VERSION 5.8 ;
BUSBITCHARS "[]" ;
DIVIDERCHAR "/" ;
UNITS
    DATABASE MICRONS 1000 ;
END UNITS

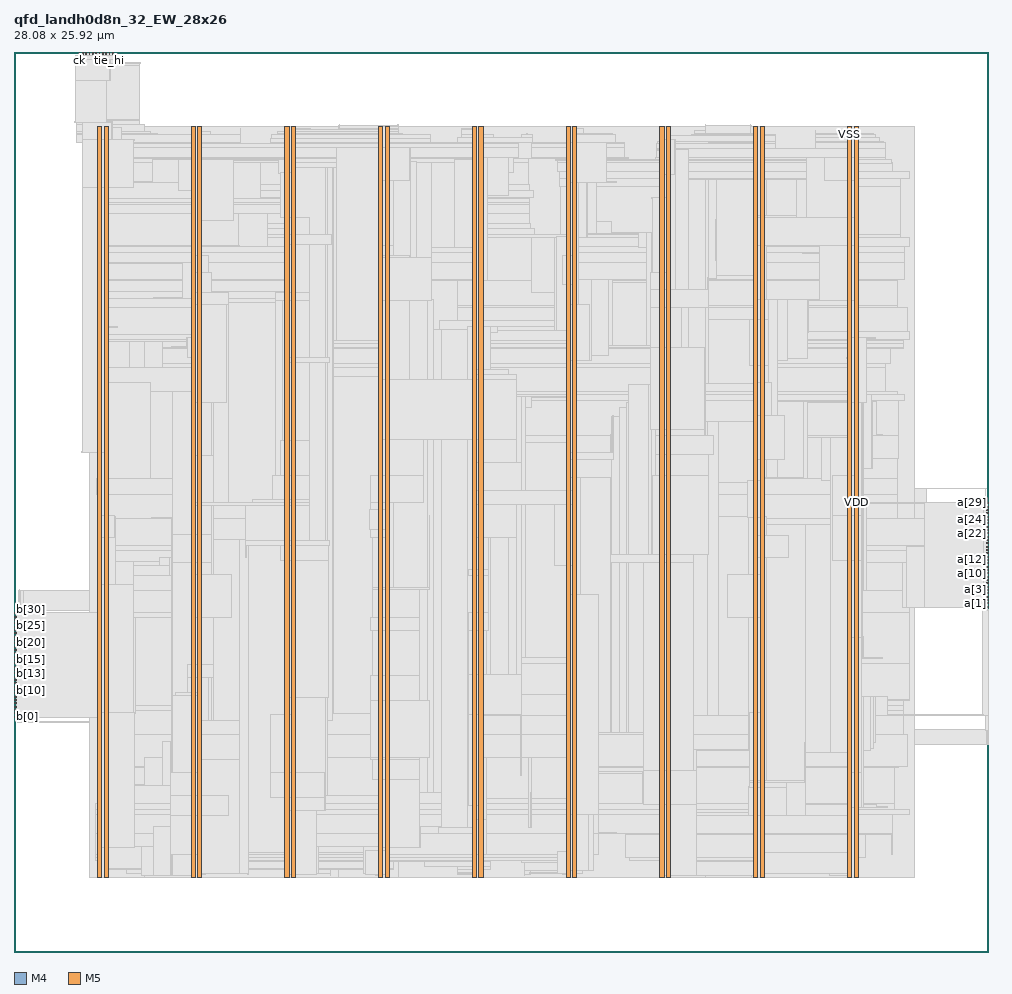
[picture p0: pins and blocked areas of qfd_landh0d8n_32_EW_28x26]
MACRO qfd_landh0d8n_32_EW_28x26
  FOREIGN qfd_landh0d8n_32_EW_28x26 0 0 ;
  CLASS BLOCK ;
  SIZE 28.08 BY 25.92 ;
  PIN a[0]
    DIRECTION INPUT ;
    USE SIGNAL ;
    PORT
      LAYER M4 ;
        RECT  27.996 9.936 28.08 9.96 ;
    END
  END a[0]
  PIN a[10]
    DIRECTION INPUT ;
    USE SIGNAL ;
    PORT
      LAYER M4 ;
        RECT  27.996 10.896 28.08 10.92 ;
    END
  END a[10]
  PIN a[11]
    DIRECTION INPUT ;
    USE SIGNAL ;
    PORT
      LAYER M4 ;
        RECT  27.996 10.992 28.08 11.016 ;
    END
  END a[11]
  PIN a[12]
    DIRECTION INPUT ;
    USE SIGNAL ;
    PORT
      LAYER M4 ;
        RECT  27.996 11.088 28.08 11.112 ;
    END
  END a[12]
  PIN a[13]
    DIRECTION INPUT ;
    USE SIGNAL ;
    PORT
      LAYER M4 ;
        RECT  27.996 11.184 28.08 11.208 ;
    END
  END a[13]
  PIN a[14]
    DIRECTION INPUT ;
    USE SIGNAL ;
    PORT
      LAYER M4 ;
        RECT  27.996 11.28 28.08 11.304 ;
    END
  END a[14]
  PIN a[15]
    DIRECTION INPUT ;
    USE SIGNAL ;
    PORT
      LAYER M4 ;
        RECT  27.996 11.376 28.08 11.4 ;
    END
  END a[15]
  PIN a[16]
    DIRECTION INPUT ;
    USE SIGNAL ;
    PORT
      LAYER M4 ;
        RECT  27.996 11.472 28.08 11.496 ;
    END
  END a[16]
  PIN a[17]
    DIRECTION INPUT ;
    USE SIGNAL ;
    PORT
      LAYER M4 ;
        RECT  27.996 11.568 28.08 11.592 ;
    END
  END a[17]
  PIN a[18]
    DIRECTION INPUT ;
    USE SIGNAL ;
    PORT
      LAYER M4 ;
        RECT  27.996 11.664 28.08 11.688 ;
    END
  END a[18]
  PIN a[19]
    DIRECTION INPUT ;
    USE SIGNAL ;
    PORT
      LAYER M4 ;
        RECT  27.996 11.76 28.08 11.784 ;
    END
  END a[19]
  PIN a[1]
    DIRECTION INPUT ;
    USE SIGNAL ;
    PORT
      LAYER M4 ;
        RECT  27.996 10.032 28.08 10.056 ;
    END
  END a[1]
  PIN a[20]
    DIRECTION INPUT ;
    USE SIGNAL ;
    PORT
      LAYER M4 ;
        RECT  27.996 11.856 28.08 11.88 ;
    END
  END a[20]
  PIN a[21]
    DIRECTION INPUT ;
    USE SIGNAL ;
    PORT
      LAYER M4 ;
        RECT  27.996 11.952 28.08 11.976 ;
    END
  END a[21]
  PIN a[22]
    DIRECTION INPUT ;
    USE SIGNAL ;
    PORT
      LAYER M4 ;
        RECT  27.996 12.048 28.08 12.072 ;
    END
  END a[22]
  PIN a[23]
    DIRECTION INPUT ;
    USE SIGNAL ;
    PORT
      LAYER M4 ;
        RECT  27.996 12.144 28.08 12.168 ;
    END
  END a[23]
  PIN a[24]
    DIRECTION INPUT ;
    USE SIGNAL ;
    PORT
      LAYER M4 ;
        RECT  27.996 12.24 28.08 12.264 ;
    END
  END a[24]
  PIN a[25]
    DIRECTION INPUT ;
    USE SIGNAL ;
    PORT
      LAYER M4 ;
        RECT  27.996 12.336 28.08 12.36 ;
    END
  END a[25]
  PIN a[26]
    DIRECTION INPUT ;
    USE SIGNAL ;
    PORT
      LAYER M4 ;
        RECT  27.996 12.432 28.08 12.456 ;
    END
  END a[26]
  PIN a[27]
    DIRECTION INPUT ;
    USE SIGNAL ;
    PORT
      LAYER M4 ;
        RECT  27.996 12.528 28.08 12.552 ;
    END
  END a[27]
  PIN a[28]
    DIRECTION INPUT ;
    USE SIGNAL ;
    PORT
      LAYER M4 ;
        RECT  27.996 12.624 28.08 12.648 ;
    END
  END a[28]
  PIN a[29]
    DIRECTION INPUT ;
    USE SIGNAL ;
    PORT
      LAYER M4 ;
        RECT  27.996 12.72 28.08 12.744 ;
    END
  END a[29]
  PIN a[2]
    DIRECTION INPUT ;
    USE SIGNAL ;
    PORT
      LAYER M4 ;
        RECT  27.996 10.128 28.08 10.152 ;
    END
  END a[2]
  PIN a[30]
    DIRECTION INPUT ;
    USE SIGNAL ;
    PORT
      LAYER M4 ;
        RECT  27.996 12.816 28.08 12.84 ;
    END
  END a[30]
  PIN a[31]
    DIRECTION INPUT ;
    USE SIGNAL ;
    PORT
      LAYER M4 ;
        RECT  27.996 12.912 28.08 12.936 ;
    END
  END a[31]
  PIN a[3]
    DIRECTION INPUT ;
    USE SIGNAL ;
    PORT
      LAYER M4 ;
        RECT  27.996 10.224 28.08 10.248 ;
    END
  END a[3]
  PIN a[4]
    DIRECTION INPUT ;
    USE SIGNAL ;
    PORT
      LAYER M4 ;
        RECT  27.996 10.32 28.08 10.344 ;
    END
  END a[4]
  PIN a[5]
    DIRECTION INPUT ;
    USE SIGNAL ;
    PORT
      LAYER M4 ;
        RECT  27.996 10.416 28.08 10.44 ;
    END
  END a[5]
  PIN a[6]
    DIRECTION INPUT ;
    USE SIGNAL ;
    PORT
      LAYER M4 ;
        RECT  27.996 10.512 28.08 10.536 ;
    END
  END a[6]
  PIN a[7]
    DIRECTION INPUT ;
    USE SIGNAL ;
    PORT
      LAYER M4 ;
        RECT  27.996 10.608 28.08 10.632 ;
    END
  END a[7]
  PIN a[8]
    DIRECTION INPUT ;
    USE SIGNAL ;
    PORT
      LAYER M4 ;
        RECT  27.996 10.704 28.08 10.728 ;
    END
  END a[8]
  PIN a[9]
    DIRECTION INPUT ;
    USE SIGNAL ;
    PORT
      LAYER M4 ;
        RECT  27.996 10.8 28.08 10.824 ;
    END
  END a[9]
  PIN b[0]
    DIRECTION OUTPUT ;
    USE SIGNAL ;
    PORT
      LAYER M4 ;
        RECT  0 6.768 0.084 6.792 ;
    END
  END b[0]
  PIN b[10]
    DIRECTION OUTPUT ;
    USE SIGNAL ;
    PORT
      LAYER M4 ;
        RECT  0 7.728 0.084 7.752 ;
    END
  END b[10]
  PIN b[11]
    DIRECTION OUTPUT ;
    USE SIGNAL ;
    PORT
      LAYER M4 ;
        RECT  0 7.824 0.084 7.848 ;
    END
  END b[11]
  PIN b[12]
    DIRECTION OUTPUT ;
    USE SIGNAL ;
    PORT
      LAYER M4 ;
        RECT  0 7.92 0.084 7.944 ;
    END
  END b[12]
  PIN b[13]
    DIRECTION OUTPUT ;
    USE SIGNAL ;
    PORT
      LAYER M4 ;
        RECT  0 8.016 0.084 8.04 ;
    END
  END b[13]
  PIN b[14]
    DIRECTION OUTPUT ;
    USE SIGNAL ;
    PORT
      LAYER M4 ;
        RECT  0 8.112 0.084 8.136 ;
    END
  END b[14]
  PIN b[15]
    DIRECTION OUTPUT ;
    USE SIGNAL ;
    PORT
      LAYER M4 ;
        RECT  0 8.208 0.084 8.232 ;
    END
  END b[15]
  PIN b[16]
    DIRECTION OUTPUT ;
    USE SIGNAL ;
    PORT
      LAYER M4 ;
        RECT  0 8.304 0.084 8.328 ;
    END
  END b[16]
  PIN b[17]
    DIRECTION OUTPUT ;
    USE SIGNAL ;
    PORT
      LAYER M4 ;
        RECT  0 8.4 0.084 8.424 ;
    END
  END b[17]
  PIN b[18]
    DIRECTION OUTPUT ;
    USE SIGNAL ;
    PORT
      LAYER M4 ;
        RECT  0 8.496 0.084 8.52 ;
    END
  END b[18]
  PIN b[19]
    DIRECTION OUTPUT ;
    USE SIGNAL ;
    PORT
      LAYER M4 ;
        RECT  0 8.592 0.084 8.616 ;
    END
  END b[19]
  PIN b[1]
    DIRECTION OUTPUT ;
    USE SIGNAL ;
    PORT
      LAYER M4 ;
        RECT  0 6.864 0.084 6.888 ;
    END
  END b[1]
  PIN b[20]
    DIRECTION OUTPUT ;
    USE SIGNAL ;
    PORT
      LAYER M4 ;
        RECT  0 8.688 0.084 8.712 ;
    END
  END b[20]
  PIN b[21]
    DIRECTION OUTPUT ;
    USE SIGNAL ;
    PORT
      LAYER M4 ;
        RECT  0 8.784 0.084 8.808 ;
    END
  END b[21]
  PIN b[22]
    DIRECTION OUTPUT ;
    USE SIGNAL ;
    PORT
      LAYER M4 ;
        RECT  0 8.88 0.084 8.904 ;
    END
  END b[22]
  PIN b[23]
    DIRECTION OUTPUT ;
    USE SIGNAL ;
    PORT
      LAYER M4 ;
        RECT  0 8.976 0.084 9 ;
    END
  END b[23]
  PIN b[24]
    DIRECTION OUTPUT ;
    USE SIGNAL ;
    PORT
      LAYER M4 ;
        RECT  0 9.072 0.084 9.096 ;
    END
  END b[24]
  PIN b[25]
    DIRECTION OUTPUT ;
    USE SIGNAL ;
    PORT
      LAYER M4 ;
        RECT  0 9.168 0.084 9.192 ;
    END
  END b[25]
  PIN b[26]
    DIRECTION OUTPUT ;
    USE SIGNAL ;
    PORT
      LAYER M4 ;
        RECT  0 9.264 0.084 9.288 ;
    END
  END b[26]
  PIN b[27]
    DIRECTION OUTPUT ;
    USE SIGNAL ;
    PORT
      LAYER M4 ;
        RECT  0 9.36 0.084 9.384 ;
    END
  END b[27]
  PIN b[28]
    DIRECTION OUTPUT ;
    USE SIGNAL ;
    PORT
      LAYER M4 ;
        RECT  0 9.456 0.084 9.48 ;
    END
  END b[28]
  PIN b[29]
    DIRECTION OUTPUT ;
    USE SIGNAL ;
    PORT
      LAYER M4 ;
        RECT  0 9.552 0.084 9.576 ;
    END
  END b[29]
  PIN b[2]
    DIRECTION OUTPUT ;
    USE SIGNAL ;
    PORT
      LAYER M4 ;
        RECT  0 6.96 0.084 6.984 ;
    END
  END b[2]
  PIN b[30]
    DIRECTION OUTPUT ;
    USE SIGNAL ;
    PORT
      LAYER M4 ;
        RECT  0 9.648 0.084 9.672 ;
    END
  END b[30]
  PIN b[31]
    DIRECTION OUTPUT ;
    USE SIGNAL ;
    PORT
      LAYER M4 ;
        RECT  0 9.744 0.084 9.768 ;
    END
  END b[31]
  PIN b[3]
    DIRECTION OUTPUT ;
    USE SIGNAL ;
    PORT
      LAYER M4 ;
        RECT  0 7.056 0.084 7.08 ;
    END
  END b[3]
  PIN b[4]
    DIRECTION OUTPUT ;
    USE SIGNAL ;
    PORT
      LAYER M4 ;
        RECT  0 7.152 0.084 7.176 ;
    END
  END b[4]
  PIN b[5]
    DIRECTION OUTPUT ;
    USE SIGNAL ;
    PORT
      LAYER M4 ;
        RECT  0 7.248 0.084 7.272 ;
    END
  END b[5]
  PIN b[6]
    DIRECTION OUTPUT ;
    USE SIGNAL ;
    PORT
      LAYER M4 ;
        RECT  0 7.344 0.084 7.368 ;
    END
  END b[6]
  PIN b[7]
    DIRECTION OUTPUT ;
    USE SIGNAL ;
    PORT
      LAYER M4 ;
        RECT  0 7.44 0.084 7.464 ;
    END
  END b[7]
  PIN b[8]
    DIRECTION OUTPUT ;
    USE SIGNAL ;
    PORT
      LAYER M4 ;
        RECT  0 7.536 0.084 7.56 ;
    END
  END b[8]
  PIN b[9]
    DIRECTION OUTPUT ;
    USE SIGNAL ;
    PORT
      LAYER M4 ;
        RECT  0 7.632 0.084 7.656 ;
    END
  END b[9]
  PIN ck
    DIRECTION INPUT ;
    USE SIGNAL ;
    PORT
      LAYER M5 ;
        RECT  1.872 25.836 1.896 25.92 ;
    END
  END ck
  PIN ck_s
    DIRECTION INPUT ;
    USE SIGNAL ;
    PORT
      LAYER M5 ;
        RECT  1.968 25.836 1.992 25.92 ;
    END
  END ck_s
  PIN en
    DIRECTION INPUT ;
    USE SIGNAL ;
    PORT
      LAYER M5 ;
        RECT  2.064 25.836 2.088 25.92 ;
    END
  END en
  PIN fault
    DIRECTION OUTPUT ;
    USE SIGNAL ;
    PORT
      LAYER M5 ;
        RECT  2.16 25.836 2.184 25.92 ;
    END
  END fault
  PIN k0
    DIRECTION INPUT ;
    USE SIGNAL ;
    PORT
      LAYER M5 ;
        RECT  2.256 25.836 2.28 25.92 ;
    END
  END k0
  PIN k1
    DIRECTION INPUT ;
    USE SIGNAL ;
    PORT
      LAYER M5 ;
        RECT  2.352 25.836 2.376 25.92 ;
    END
  END k1
  PIN k2
    DIRECTION INPUT ;
    USE SIGNAL ;
    PORT
      LAYER M5 ;
        RECT  2.448 25.836 2.472 25.92 ;
    END
  END k2
  PIN k3
    DIRECTION INPUT ;
    USE SIGNAL ;
    PORT
      LAYER M5 ;
        RECT  2.544 25.836 2.568 25.92 ;
    END
  END k3
  PIN rs
    DIRECTION INPUT ;
    USE SIGNAL ;
    PORT
      LAYER M5 ;
        RECT  2.64 25.836 2.664 25.92 ;
    END
  END rs
  PIN tie_hi
    DIRECTION OUTPUT ;
    USE SIGNAL ;
    PORT
      LAYER M5 ;
        RECT  2.736 25.836 2.76 25.92 ;
    END
  END tie_hi
  PIN tie_lo
    DIRECTION OUTPUT ;
    USE SIGNAL ;
    PORT
      LAYER M5 ;
        RECT  2.832 25.836 2.856 25.92 ;
    END
  END tie_lo
  PIN VDD
    DIRECTION INOUT ;
    USE POWER ;
    PORT
      LAYER M5 ;
        RECT  24.192 2.151 24.312 23.769 ;
        RECT  21.492 2.151 21.612 23.769 ;
        RECT  18.792 2.151 18.912 23.769 ;
        RECT  16.092 2.151 16.212 23.769 ;
        RECT  13.392 2.151 13.512 23.769 ;
        RECT  10.692 2.151 10.812 23.769 ;
        RECT  7.992 2.151 8.112 23.769 ;
        RECT  5.292 2.151 5.412 23.769 ;
        RECT  2.592 2.151 2.712 23.769 ;
    END
  END VDD
  PIN VSS
    DIRECTION INOUT ;
    USE GROUND ;
    PORT
      LAYER M5 ;
        RECT  24 2.137 24.12 23.783 ;
        RECT  21.3 2.137 21.42 23.783 ;
        RECT  18.6 2.137 18.72 23.783 ;
        RECT  15.9 2.137 16.02 23.783 ;
        RECT  13.2 2.137 13.32 23.783 ;
        RECT  10.5 2.137 10.62 23.783 ;
        RECT  7.8 2.137 7.92 23.783 ;
        RECT  5.1 2.137 5.22 23.783 ;
        RECT  2.4 2.137 2.52 23.783 ;
    END
  END VSS
  OBS
    LAYER RVTN ;
     RECT  2.16 2.16 25.92 2.295 ;
     RECT  2.16 2.565 25.92 2.835 ;
     RECT  2.16 3.105 25.92 3.375 ;
     RECT  2.16 3.645 25.92 3.915 ;
     RECT  2.16 4.185 25.92 4.455 ;
     RECT  2.16 4.725 25.92 4.995 ;
     RECT  2.16 5.265 25.92 5.535 ;
     RECT  2.16 5.805 25.92 6.075 ;
     RECT  2.16 6.345 25.92 6.615 ;
     RECT  2.16 6.885 25.92 7.155 ;
     RECT  2.16 7.425 25.92 7.695 ;
     RECT  2.16 7.965 25.92 8.235 ;
     RECT  2.16 8.505 25.92 8.775 ;
     RECT  2.16 9.045 25.92 9.315 ;
     RECT  2.16 9.585 25.92 9.855 ;
     RECT  2.16 10.125 25.92 10.395 ;
     RECT  2.16 10.665 25.92 10.935 ;
     RECT  2.16 11.205 25.92 11.475 ;
     RECT  2.16 11.745 25.92 12.015 ;
     RECT  2.16 12.285 25.92 12.555 ;
     RECT  2.16 12.825 25.92 13.095 ;
     RECT  2.16 13.365 25.92 13.635 ;
     RECT  2.16 13.905 25.92 14.175 ;
     RECT  2.16 14.445 25.92 14.715 ;
     RECT  2.16 14.985 25.92 15.255 ;
     RECT  2.16 15.525 25.92 15.795 ;
     RECT  2.16 16.065 25.92 16.335 ;
     RECT  2.16 16.605 25.92 16.875 ;
     RECT  2.16 17.145 25.92 17.415 ;
     RECT  2.16 17.685 25.92 17.955 ;
     RECT  2.16 18.225 25.92 18.495 ;
     RECT  2.16 18.765 25.92 19.035 ;
     RECT  2.16 19.305 25.92 19.575 ;
     RECT  2.16 19.845 25.92 20.115 ;
     RECT  2.16 20.385 25.92 20.655 ;
     RECT  2.16 20.925 25.92 21.195 ;
     RECT  2.16 21.465 25.92 21.735 ;
     RECT  2.16 22.005 25.92 22.275 ;
     RECT  2.16 22.545 25.92 22.815 ;
     RECT  2.16 23.085 25.92 23.355 ;
     RECT  2.16 23.625 25.92 23.76 ;
    LAYER RVTP ;
     RECT  2.16 2.295 25.92 2.565 ;
     RECT  2.16 2.835 25.92 3.105 ;
     RECT  2.16 3.375 25.92 3.645 ;
     RECT  2.16 3.915 25.92 4.185 ;
     RECT  2.16 4.455 25.92 4.725 ;
     RECT  2.16 4.995 25.92 5.265 ;
     RECT  2.16 5.535 25.92 5.805 ;
     RECT  2.16 6.075 25.92 6.345 ;
     RECT  2.16 6.615 25.92 6.885 ;
     RECT  2.16 7.155 25.92 7.425 ;
     RECT  2.16 7.695 25.92 7.965 ;
     RECT  2.16 8.235 25.92 8.505 ;
     RECT  2.16 8.775 25.92 9.045 ;
     RECT  2.16 9.315 25.92 9.585 ;
     RECT  2.16 9.855 25.92 10.125 ;
     RECT  2.16 10.395 25.92 10.665 ;
     RECT  2.16 10.935 25.92 11.205 ;
     RECT  2.16 11.475 25.92 11.745 ;
     RECT  2.16 12.015 25.92 12.285 ;
     RECT  2.16 12.555 25.92 12.825 ;
     RECT  2.16 13.095 25.92 13.365 ;
     RECT  2.16 13.635 25.92 13.905 ;
     RECT  2.16 14.175 25.92 14.445 ;
     RECT  2.16 14.715 25.92 14.985 ;
     RECT  2.16 15.255 25.92 15.525 ;
     RECT  2.16 15.795 25.92 16.065 ;
     RECT  2.16 16.335 25.92 16.605 ;
     RECT  2.16 16.875 25.92 17.145 ;
     RECT  2.16 17.415 25.92 17.685 ;
     RECT  2.16 17.955 25.92 18.225 ;
     RECT  2.16 18.495 25.92 18.765 ;
     RECT  2.16 19.035 25.92 19.305 ;
     RECT  2.16 19.575 25.92 19.845 ;
     RECT  2.16 20.115 25.92 20.385 ;
     RECT  2.16 20.655 25.92 20.925 ;
     RECT  2.16 21.195 25.92 21.465 ;
     RECT  2.16 21.735 25.92 22.005 ;
     RECT  2.16 22.275 25.92 22.545 ;
     RECT  2.16 22.815 25.92 23.085 ;
     RECT  2.16 23.355 25.92 23.625 ;
    LAYER M1 ;
     RECT  2.16 2.151 25.92 23.769 ;
    LAYER M2 ;
     RECT  0.103 9.828 0.139 9.846 ;
     RECT  0.139 9.828 0.175 10.422 ;
     RECT  0.103 6.624 0.203 8.226 ;
     RECT  0.203 7.398 0.239 7.686 ;
     RECT  0.175 9.63 0.275 10.422 ;
     RECT  0.239 7.398 1.147 7.416 ;
     RECT  0.535 8.514 1.147 8.532 ;
     RECT  1.147 7.398 1.175 8.532 ;
     RECT  0.203 6.624 2.16 6.642 ;
     RECT  1.175 7.398 2.16 8.064 ;
     RECT  0.275 9.828 2.16 10.422 ;
     RECT  1.795 23.328 2.16 23.346 ;
     RECT  2.16 2.151 2.551 23.769 ;
     RECT  2.551 2.151 3.767 23.814 ;
     RECT  3.767 2.151 9.355 23.769 ;
     RECT  9.355 2.151 11.075 23.814 ;
     RECT  11.075 2.151 19.903 23.769 ;
     RECT  19.903 2.151 21.227 23.814 ;
     RECT  21.227 2.151 25.92 23.769 ;
     RECT  25.92 10.17 26.267 13.356 ;
     RECT  26.267 10.17 27.383 12.546 ;
     RECT  27.383 10.44 27.455 12.51 ;
     RECT  27.455 10.44 27.491 11.934 ;
     RECT  25.92 5.976 27.995 6.408 ;
     RECT  27.491 10.44 27.995 11.538 ;
     RECT  26.267 13.338 27.995 13.356 ;
     RECT  27.995 5.976 28.067 5.994 ;
    LAYER M3 ;
     RECT  5.115 2.143 5.205 2.191 ;
     RECT  10.515 2.143 10.605 2.191 ;
     RECT  24.015 2.143 24.105 2.191 ;
     RECT  3.672 2.191 4.158 2.203 ;
     RECT  5.076 2.191 5.205 2.203 ;
     RECT  3.672 2.203 5.205 2.227 ;
     RECT  13.215 2.143 13.305 2.227 ;
     RECT  15.915 2.143 16.005 2.227 ;
     RECT  14.688 2.191 14.706 2.24 ;
     RECT  9.108 2.191 9.126 2.251 ;
     RECT  10.404 2.191 10.605 2.251 ;
     RECT  12.78 2.227 13.305 2.251 ;
     RECT  21.315 2.143 21.405 2.251 ;
     RECT  23.472 2.191 24.105 2.251 ;
     RECT  3.672 2.227 5.526 2.263 ;
     RECT  15.804 2.227 16.005 2.263 ;
     RECT  18.615 2.143 18.705 2.263 ;
     RECT  21.315 2.251 21.69 2.263 ;
     RECT  18.615 2.263 19.422 2.299 ;
     RECT  20.556 2.191 20.574 2.299 ;
     RECT  21.315 2.263 22.23 2.299 ;
     RECT  14.688 2.24 14.886 2.335 ;
     RECT  15.804 2.263 16.362 2.335 ;
     RECT  18.615 2.299 19.566 2.335 ;
     RECT  14.688 2.335 16.362 2.347 ;
     RECT  2.415 2.143 2.505 2.371 ;
     RECT  3.24 2.263 5.526 2.371 ;
     RECT  6.732 2.227 6.75 2.371 ;
     RECT  7.815 2.143 7.905 2.371 ;
     RECT  8.712 2.251 9.126 2.371 ;
     RECT  10.116 2.251 10.605 2.371 ;
     RECT  12.78 2.251 13.374 2.371 ;
     RECT  23.328 2.251 24.105 2.371 ;
     RECT  6.732 2.371 7.905 2.413 ;
     RECT  8.712 2.371 10.926 2.413 ;
     RECT  23.328 2.371 24.174 2.413 ;
     RECT  12.78 2.371 13.734 2.461 ;
     RECT  18.615 2.335 19.782 2.461 ;
     RECT  20.556 2.299 22.23 2.461 ;
     RECT  23.328 2.413 24.297 2.497 ;
     RECT  14.688 2.347 16.686 2.569 ;
     RECT  18.615 2.461 22.23 2.569 ;
     RECT  23.076 2.497 24.297 2.569 ;
     RECT  6.732 2.413 10.926 2.605 ;
     RECT  11.808 2.461 13.734 2.605 ;
     RECT  2.415 2.371 5.526 2.641 ;
     RECT  6.624 2.605 13.734 2.641 ;
     RECT  14.616 2.569 16.686 2.641 ;
     RECT  18.615 2.569 24.297 2.641 ;
     RECT  2.34 2.641 5.526 2.731 ;
     RECT  6.624 2.641 16.686 2.731 ;
     RECT  17.712 2.641 24.297 2.731 ;
     RECT  2.34 2.731 16.686 2.803 ;
     RECT  17.604 2.731 24.534 3.379 ;
     RECT  25.272 2.803 25.29 3.379 ;
     RECT  2.34 2.803 16.83 3.403 ;
     RECT  17.604 3.379 25.29 3.403 ;
     RECT  2.34 3.403 25.29 3.955 ;
     RECT  2.34 3.955 25.794 4.109 ;
     RECT  2.34 4.109 25.362 4.289 ;
     RECT  2.415 4.289 25.362 5.305 ;
     RECT  2.415 5.305 25.47 5.341 ;
     RECT  2.415 5.341 25.722 6.269 ;
     RECT  28.044 5.971 28.062 6.385 ;
     RECT  27.972 6.385 28.062 6.811 ;
     RECT  0.108 6.619 0.126 6.859 ;
     RECT  2.415 6.269 25.614 6.961 ;
     RECT  2.304 6.961 25.614 7.085 ;
     RECT  2.376 7.085 25.614 7.231 ;
     RECT  2.376 7.231 25.794 7.259 ;
     RECT  0.108 6.859 0.342 7.393 ;
     RECT  0.108 7.393 0.558 7.483 ;
     RECT  0.108 7.483 1.17 7.757 ;
     RECT  2.415 7.259 25.794 8.299 ;
     RECT  0.108 7.757 0.234 8.509 ;
     RECT  1.152 7.757 1.17 8.509 ;
     RECT  0.108 8.509 1.17 8.537 ;
     RECT  0.108 8.537 0.558 8.621 ;
     RECT  0.108 8.621 0.234 9.451 ;
     RECT  0.108 9.451 0.414 9.581 ;
     RECT  0.108 9.581 0.342 9.677 ;
     RECT  2.304 8.299 25.794 9.773 ;
     RECT  0.108 9.677 0.162 9.851 ;
     RECT  27.9 6.811 28.062 9.869 ;
     RECT  27.9 9.869 27.99 10.165 ;
     RECT  2.415 9.773 25.794 10.399 ;
     RECT  0.144 9.851 0.162 10.427 ;
     RECT  2.415 10.399 26.262 10.829 ;
     RECT  27.36 10.165 27.99 10.891 ;
     RECT  26.748 10.891 27.99 10.931 ;
     RECT  27.36 10.931 27.99 11.543 ;
     RECT  2.415 10.829 25.794 11.551 ;
     RECT  2.415 11.551 26.262 11.713 ;
     RECT  27.36 11.543 27.486 11.713 ;
     RECT  2.415 11.713 27.486 12.479 ;
     RECT  26.244 12.479 27.486 12.551 ;
     RECT  27.36 12.551 27.486 12.557 ;
     RECT  27.432 12.557 27.486 12.653 ;
     RECT  26.244 12.551 26.262 12.893 ;
     RECT  2.415 12.479 25.434 13.171 ;
     RECT  27.972 12.715 27.99 13.361 ;
     RECT  2.376 13.171 25.434 13.631 ;
     RECT  2.415 13.631 25.434 14.215 ;
     RECT  2.415 14.215 25.47 14.881 ;
     RECT  2.34 14.881 25.47 15.871 ;
     RECT  2.34 15.871 25.65 16.061 ;
     RECT  2.34 16.061 25.434 16.133 ;
     RECT  2.34 16.133 25.11 16.835 ;
     RECT  4.284 16.835 25.11 16.951 ;
     RECT  4.284 16.951 25.254 17.383 ;
     RECT  4.284 17.383 25.614 17.411 ;
     RECT  6.84 17.411 25.614 17.519 ;
     RECT  2.34 16.835 3.33 17.581 ;
     RECT  4.284 17.411 5.958 17.581 ;
     RECT  12.24 17.519 25.614 17.609 ;
     RECT  2.34 17.581 5.958 17.651 ;
     RECT  17.1 17.609 25.614 17.653 ;
     RECT  2.415 17.651 5.958 17.789 ;
     RECT  17.1 17.653 25.794 17.879 ;
     RECT  12.24 17.609 16.197 18.185 ;
     RECT  6.84 17.519 11.502 18.229 ;
     RECT  6.408 18.229 11.502 18.301 ;
     RECT  17.1 17.879 25.722 18.563 ;
     RECT  2.415 17.789 5.67 18.571 ;
     RECT  6.408 18.301 12.006 18.571 ;
     RECT  12.78 18.185 16.197 18.571 ;
     RECT  12.78 18.571 16.254 18.619 ;
     RECT  17.1 18.563 25.434 18.619 ;
     RECT  2.415 18.571 12.006 18.811 ;
     RECT  2.34 18.811 12.006 19.031 ;
     RECT  2.415 19.031 12.006 19.345 ;
     RECT  12.78 18.619 25.434 19.345 ;
     RECT  2.415 19.345 25.434 19.381 ;
     RECT  2.415 19.381 25.65 19.849 ;
     RECT  2.34 19.849 25.65 20.147 ;
     RECT  2.415 20.147 25.65 20.309 ;
     RECT  7.308 20.309 25.65 20.317 ;
     RECT  2.415 20.309 6.498 20.345 ;
     RECT  7.308 20.317 25.794 20.579 ;
     RECT  7.308 20.579 25.542 20.651 ;
     RECT  7.308 20.651 14.994 20.849 ;
     RECT  7.308 20.849 14.886 20.993 ;
     RECT  2.415 20.345 6.462 21.271 ;
     RECT  7.308 20.993 14.85 21.271 ;
     RECT  2.415 21.271 14.85 21.541 ;
     RECT  2.304 21.541 14.85 21.581 ;
     RECT  2.376 21.581 14.85 21.695 ;
     RECT  7.092 21.695 14.85 21.739 ;
     RECT  7.092 21.739 14.958 21.929 ;
     RECT  15.732 20.651 25.542 22.045 ;
     RECT  7.092 21.929 14.85 22.109 ;
     RECT  15.696 22.045 25.542 22.279 ;
     RECT  15.696 22.279 25.794 22.469 ;
     RECT  15.696 22.469 25.29 22.477 ;
     RECT  15.66 22.477 25.29 22.739 ;
     RECT  2.376 21.695 6.318 22.747 ;
     RECT  7.092 22.109 14.814 22.747 ;
     RECT  15.66 22.739 25.254 22.783 ;
     RECT  15.588 22.783 25.254 22.811 ;
     RECT  18.468 22.811 25.254 22.829 ;
     RECT  2.376 22.747 14.814 22.843 ;
     RECT  15.588 22.811 17.694 22.843 ;
     RECT  2.376 22.843 17.694 22.883 ;
     RECT  18.468 22.829 25.11 22.883 ;
     RECT  18.504 22.883 25.11 23.153 ;
     RECT  2.376 22.883 17.586 23.161 ;
     RECT  2.34 23.161 17.586 23.279 ;
     RECT  18.504 23.153 21.942 23.279 ;
     RECT  7.38 23.279 17.586 23.309 ;
     RECT  7.38 23.309 15.174 23.315 ;
     RECT  15.912 23.309 17.586 23.315 ;
     RECT  23.076 23.153 25.11 23.315 ;
     RECT  2.34 23.279 6.534 23.323 ;
     RECT  18.54 23.279 21.942 23.351 ;
     RECT  23.076 23.315 25.038 23.351 ;
     RECT  7.38 23.315 12.006 23.423 ;
     RECT  12.78 23.315 14.922 23.459 ;
     RECT  23.076 23.351 24.93 23.459 ;
     RECT  18.615 23.351 21.942 23.507 ;
     RECT  1.8 23.323 6.534 23.549 ;
     RECT  7.416 23.423 12.006 23.549 ;
     RECT  12.888 23.459 13.806 23.549 ;
     RECT  14.616 23.459 14.922 23.549 ;
     RECT  15.915 23.315 17.334 23.549 ;
     RECT  19.512 23.507 21.942 23.549 ;
     RECT  23.076 23.459 24.822 23.549 ;
     RECT  1.8 23.549 4.122 23.585 ;
     RECT  7.596 23.549 11.178 23.585 ;
     RECT  14.76 23.549 14.778 23.585 ;
     RECT  15.915 23.549 17.226 23.585 ;
     RECT  19.584 23.549 21.474 23.585 ;
     RECT  23.076 23.549 24.75 23.585 ;
     RECT  1.8 23.585 3.942 23.621 ;
     RECT  5.115 23.549 5.67 23.621 ;
     RECT  7.596 23.585 11.07 23.621 ;
     RECT  19.584 23.585 19.926 23.657 ;
     RECT  23.076 23.585 23.094 23.657 ;
     RECT  7.815 23.621 11.07 23.693 ;
     RECT  12.888 23.549 13.374 23.693 ;
     RECT  6.516 23.549 6.534 23.729 ;
     RECT  7.815 23.693 8.55 23.729 ;
     RECT  9.36 23.693 11.07 23.729 ;
     RECT  12.888 23.693 13.305 23.729 ;
     RECT  15.915 23.585 16.398 23.729 ;
     RECT  5.115 23.621 5.205 23.777 ;
     RECT  7.815 23.729 7.905 23.777 ;
     RECT  10.515 23.729 11.07 23.777 ;
     RECT  13.215 23.729 13.305 23.777 ;
     RECT  15.915 23.729 16.005 23.777 ;
     RECT  18.615 23.507 18.705 23.777 ;
     RECT  21.204 23.585 21.405 23.777 ;
     RECT  24.015 23.585 24.105 23.777 ;
     RECT  1.8 23.621 3.762 23.819 ;
     RECT  9.36 23.729 9.378 23.819 ;
     RECT  11.052 23.777 11.07 23.819 ;
     RECT  19.908 23.657 19.926 23.819 ;
     RECT  21.204 23.777 21.222 23.819 ;
     RECT  1.8 23.819 3.618 23.933 ;
     RECT  2.34 23.933 3.618 23.981 ;
     RECT  2.376 23.981 3.618 25.531 ;
     RECT  2.268 25.531 3.618 25.613 ;
     RECT  2.268 25.613 3.006 25.709 ;
     RECT  2.988 25.709 3.006 25.757 ;
    LAYER M4 ;
     RECT  1.765 25.776 1.861 25.8 ;
     RECT  1.957 14.4 2.101 14.424 ;
     RECT  1.861 25.488 2.291 25.8 ;
     RECT  2.285 18.816 2.293 18.84 ;
     RECT  1.745 23.904 2.296 23.928 ;
     RECT  2.291 25.488 2.365 25.752 ;
     RECT  2.296 23.904 2.387 23.976 ;
     RECT  0.06 6.768 2.408 9.768 ;
     RECT  2.101 14.4 2.408 15.24 ;
     RECT  2.329 16.368 2.408 16.392 ;
     RECT  2.293 17.616 2.408 18.84 ;
     RECT  2.252 21.552 2.408 21.576 ;
     RECT  2.387 23.904 2.408 23.928 ;
     RECT  2.408 2.148 2.512 23.928 ;
     RECT  2.512 2.418 2.704 23.928 ;
     RECT  2.365 25.104 2.771 25.752 ;
     RECT  2.704 23.376 2.837 23.928 ;
     RECT  2.704 6.864 2.915 12.552 ;
     RECT  2.915 12.528 2.917 12.552 ;
     RECT  2.704 18 2.981 18.024 ;
     RECT  2.771 25.584 3.017 25.752 ;
     RECT  2.837 23.376 3.089 23.736 ;
     RECT  2.915 6.864 3.443 11.256 ;
     RECT  2.704 22.032 3.443 22.2 ;
     RECT  3.089 23.376 3.457 23.4 ;
     RECT  3.443 6.864 3.493 9.624 ;
     RECT  3.017 25.584 3.629 25.608 ;
     RECT  2.704 2.418 3.661 3.048 ;
     RECT  2.704 4.8 3.769 4.824 ;
     RECT  2.704 13.632 3.917 16.392 ;
     RECT  3.443 22.176 3.985 22.2 ;
     RECT  3.661 2.208 4.021 3.048 ;
     RECT  3.443 11.136 4.201 11.256 ;
     RECT  3.769 4.8 4.273 5.592 ;
     RECT  4.201 11.136 4.489 11.352 ;
     RECT  4.021 2.208 4.501 3.624 ;
     RECT  4.273 4.8 4.501 6.072 ;
     RECT  3.493 7.104 4.525 9.624 ;
     RECT  4.489 10.848 4.525 11.352 ;
     RECT  4.501 2.208 4.549 6.072 ;
     RECT  4.525 7.104 4.549 11.352 ;
     RECT  3.949 12.48 4.549 12.504 ;
     RECT  4.549 2.208 4.561 12.504 ;
     RECT  3.917 13.632 4.561 16.152 ;
     RECT  3.985 22.176 4.741 22.824 ;
     RECT  4.021 18.816 4.849 18.84 ;
     RECT  2.704 19.824 4.849 19.848 ;
     RECT  4.525 17.424 4.957 17.448 ;
     RECT  4.957 17.424 4.993 17.688 ;
     RECT  4.561 2.208 5.108 16.152 ;
     RECT  4.993 17.136 5.108 17.688 ;
     RECT  4.849 18.816 5.108 19.848 ;
     RECT  4.741 21.936 5.108 22.824 ;
     RECT  5.108 2.148 5.212 23.772 ;
     RECT  5.212 2.256 5.404 23.502 ;
     RECT  5.404 6.672 5.603 20.04 ;
     RECT  5.603 6.672 5.699 19.56 ;
     RECT  5.699 6.672 5.753 18.984 ;
     RECT  5.753 12.912 6.179 18.984 ;
     RECT  5.404 21.072 6.329 22.824 ;
     RECT  5.404 2.256 6.505 5.544 ;
     RECT  5.753 6.672 6.505 11.88 ;
     RECT  6.505 2.256 6.761 11.88 ;
     RECT  6.179 12.912 7.525 18.696 ;
     RECT  6.329 22.8 7.628 22.824 ;
     RECT  7.525 12.912 7.732 18.984 ;
     RECT  6.761 2.88 7.801 11.88 ;
     RECT  7.801 2.496 7.808 11.88 ;
     RECT  7.732 12.864 7.808 18.984 ;
     RECT  7.669 21.168 7.808 21.192 ;
     RECT  7.628 22.416 7.808 22.824 ;
     RECT  7.808 2.148 7.912 23.772 ;
     RECT  7.912 2.256 8.104 23.502 ;
     RECT  8.104 2.256 8.764 3.048 ;
     RECT  8.104 4.08 8.985 22.584 ;
     RECT  8.985 4.512 9.029 22.584 ;
     RECT  9.029 6.672 9.173 22.584 ;
     RECT  9.173 6.864 9.209 22.584 ;
     RECT  9.209 17.616 9.277 22.584 ;
     RECT  8.764 2.88 10.076 3.048 ;
     RECT  10.076 2.256 10.508 3.048 ;
     RECT  9.029 4.512 10.508 5.592 ;
     RECT  9.209 6.864 10.508 16.584 ;
     RECT  9.277 17.616 10.508 23.16 ;
     RECT  10.508 2.148 10.612 23.772 ;
     RECT  10.612 2.418 10.804 23.502 ;
     RECT  10.804 6.912 10.931 23.16 ;
     RECT  10.931 19.968 11.411 23.16 ;
     RECT  11.411 19.968 11.585 22.776 ;
     RECT  10.804 3.024 11.699 3.624 ;
     RECT  10.804 4.608 11.905 5.64 ;
     RECT  10.931 6.912 11.905 18.792 ;
     RECT  11.585 19.968 12.035 22.728 ;
     RECT  11.905 4.608 12.081 18.792 ;
     RECT  11.699 3.408 12.233 3.624 ;
     RECT  12.233 3.6 12.301 3.624 ;
     RECT  12.081 4.608 12.301 17.928 ;
     RECT  12.035 20.304 12.697 22.728 ;
     RECT  12.301 3.6 13.057 17.928 ;
     RECT  12.769 2.256 13.208 2.28 ;
     RECT  13.057 3.6 13.208 18.024 ;
     RECT  12.697 20.304 13.208 22.824 ;
     RECT  13.208 2.148 13.312 23.772 ;
     RECT  13.312 2.256 13.385 23.502 ;
     RECT  13.385 2.418 13.504 23.502 ;
     RECT  13.504 2.832 13.619 5.592 ;
     RECT  13.504 19.344 13.637 22.872 ;
     RECT  13.504 6.816 13.709 18.024 ;
     RECT  13.709 17.856 13.925 18.024 ;
     RECT  13.709 6.816 14.243 16.776 ;
     RECT  13.637 21.792 14.249 22.872 ;
     RECT  14.249 22.464 14.393 22.872 ;
     RECT  14.243 6.816 14.483 16.632 ;
     RECT  14.393 22.848 14.533 22.872 ;
     RECT  14.483 6.816 14.627 16.008 ;
     RECT  14.627 8.496 14.717 16.008 ;
     RECT  13.619 4.416 14.828 5.592 ;
     RECT  13.637 19.344 14.893 20.568 ;
     RECT  14.717 15.696 14.897 16.008 ;
     RECT  14.533 22.848 14.897 23.304 ;
     RECT  14.828 3.6 14.915 5.592 ;
     RECT  13.925 17.904 15.577 18.024 ;
     RECT  14.893 19.008 15.577 20.568 ;
     RECT  15.577 17.904 15.616 20.568 ;
     RECT  14.857 2.256 15.649 2.28 ;
     RECT  15.649 2.256 15.908 2.904 ;
     RECT  14.915 4.416 15.908 5.592 ;
     RECT  14.627 6.816 15.908 7.416 ;
     RECT  14.717 8.496 15.908 14.664 ;
     RECT  14.897 15.984 15.908 16.008 ;
     RECT  15.616 17.904 15.908 20.616 ;
     RECT  14.897 23.28 15.908 23.304 ;
     RECT  15.908 2.148 16.012 23.772 ;
     RECT  16.012 2.352 16.204 23.502 ;
     RECT  16.204 17.04 16.265 23.304 ;
     RECT  16.204 2.352 16.301 14.376 ;
     RECT  16.265 20.592 16.481 23.304 ;
     RECT  16.301 2.352 16.499 5.304 ;
     RECT  16.481 20.592 16.517 22.2 ;
     RECT  16.499 5.136 16.553 5.304 ;
     RECT  16.265 17.04 16.633 19.368 ;
     RECT  16.499 2.352 16.697 4.008 ;
     RECT  16.517 20.688 16.769 22.2 ;
     RECT  16.697 3.408 16.835 4.008 ;
     RECT  16.481 23.28 17.075 23.304 ;
     RECT  16.633 17.184 17.129 19.368 ;
     RECT  16.301 6.336 17.18 14.376 ;
     RECT  16.769 20.688 17.201 21.048 ;
     RECT  17.18 6.336 17.221 14.904 ;
     RECT  17.129 17.472 17.237 19.368 ;
     RECT  16.835 3.408 17.345 3.432 ;
     RECT  16.769 22.176 17.345 22.2 ;
     RECT  17.221 6.336 17.449 15.432 ;
     RECT  17.449 6.336 17.629 15.672 ;
     RECT  17.629 6.336 17.701 15.816 ;
     RECT  17.201 20.688 17.989 20.712 ;
     RECT  16.553 5.136 18.092 5.208 ;
     RECT  17.237 17.472 18.205 19.272 ;
     RECT  17.989 20.304 18.205 20.712 ;
     RECT  18.092 4.272 18.277 5.208 ;
     RECT  17.701 6.336 18.277 16.344 ;
     RECT  18.277 4.272 18.349 16.344 ;
     RECT  18.205 17.472 18.349 20.712 ;
     RECT  18.349 4.272 18.608 20.712 ;
     RECT  18.373 21.696 18.608 21.72 ;
     RECT  18.493 23.088 18.608 23.112 ;
     RECT  18.608 2.148 18.712 23.772 ;
     RECT  18.712 2.208 18.904 23.502 ;
     RECT  18.904 14.352 19.043 23.4 ;
     RECT  18.904 3.936 19.139 13.32 ;
     RECT  19.043 14.352 19.433 23.112 ;
     RECT  19.139 5.136 19.469 13.32 ;
     RECT  19.469 5.184 19.505 13.32 ;
     RECT  19.505 5.184 19.667 5.832 ;
     RECT  19.433 14.352 19.907 22.248 ;
     RECT  19.505 6.816 19.969 13.32 ;
     RECT  19.907 14.352 19.969 15.288 ;
     RECT  19.907 16.368 20.003 22.248 ;
     RECT  20.003 19.392 20.225 22.248 ;
     RECT  19.969 6.816 20.297 15.288 ;
     RECT  19.139 3.936 21.157 4.008 ;
     RECT  19.667 5.808 21.157 5.832 ;
     RECT  20.297 6.816 21.157 12.552 ;
     RECT  18.904 2.208 21.308 2.616 ;
     RECT  21.157 3.936 21.308 4.776 ;
     RECT  21.157 5.808 21.308 12.552 ;
     RECT  20.297 13.536 21.308 15.288 ;
     RECT  20.003 16.368 21.308 18.216 ;
     RECT  20.225 19.488 21.308 22.248 ;
     RECT  20.005 23.328 21.308 23.352 ;
     RECT  21.308 2.148 21.412 23.772 ;
     RECT  21.412 2.256 21.604 23.502 ;
     RECT  21.604 3.936 21.665 12.552 ;
     RECT  21.604 13.68 21.665 22.248 ;
     RECT  21.665 13.68 21.989 18.792 ;
     RECT  21.989 17.04 22.277 18.792 ;
     RECT  21.665 20.352 22.547 22.248 ;
     RECT  21.989 13.68 22.741 15.864 ;
     RECT  21.665 3.936 22.787 12.312 ;
     RECT  22.547 21.12 22.813 22.248 ;
     RECT  22.741 13.632 22.853 15.864 ;
     RECT  22.277 17.088 22.853 18.792 ;
     RECT  22.853 17.856 22.889 18.792 ;
     RECT  22.853 13.632 23.245 14.808 ;
     RECT  22.787 5.76 23.516 12.312 ;
     RECT  23.245 13.584 23.516 14.808 ;
     RECT  21.604 2.256 24.008 2.856 ;
     RECT  22.787 3.936 24.008 4.248 ;
     RECT  23.516 5.76 24.008 14.808 ;
     RECT  22.853 15.84 24.008 15.864 ;
     RECT  23.965 17.088 24.008 17.112 ;
     RECT  22.889 18.768 24.008 18.792 ;
     RECT  22.705 20.112 24.008 20.136 ;
     RECT  22.813 21.12 24.008 22.872 ;
     RECT  24.008 2.148 24.112 23.772 ;
     RECT  24.112 2.418 24.304 23.502 ;
     RECT  24.304 4.176 24.401 16.056 ;
     RECT  24.401 8.448 24.445 16.056 ;
     RECT  24.401 4.176 24.46 7.368 ;
     RECT  24.445 8.448 24.46 9.096 ;
     RECT  24.445 10.416 24.473 16.056 ;
     RECT  24.473 10.416 24.545 12.936 ;
     RECT  24.304 17.088 24.563 17.688 ;
     RECT  24.46 5.808 24.653 7.368 ;
     RECT  24.473 13.92 24.689 16.056 ;
     RECT  24.689 13.92 24.725 15.864 ;
     RECT  24.653 5.856 24.761 7.368 ;
     RECT  24.761 6.048 24.797 7.368 ;
     RECT  24.563 17.664 24.797 17.688 ;
     RECT  24.46 4.176 24.833 4.248 ;
     RECT  24.725 14.88 24.833 15.864 ;
     RECT  24.46 8.448 25.013 8.472 ;
     RECT  24.833 14.88 25.013 14.904 ;
     RECT  24.833 4.176 25.157 4.2 ;
     RECT  24.797 6.816 25.157 7.368 ;
     RECT  24.304 22.704 25.265 22.824 ;
     RECT  25.265 22.704 25.301 22.728 ;
     RECT  24.545 10.416 25.585 11.208 ;
     RECT  25.585 9.936 25.693 11.208 ;
     RECT  25.693 9.936 26.233 11.688 ;
     RECT  24.545 12.912 26.233 12.936 ;
     RECT  26.233 9.936 27.925 12.936 ;
     RECT  25.157 6.816 27.929 6.84 ;
     RECT  27.925 9.84 28.044 12.936 ;
     RECT  28.044 9.84 28.073 9.864 ;
    LAYER M5 ;
     RECT  2.4 2.137 2.52 2.151 ;
     RECT  5.1 2.137 5.22 2.151 ;
     RECT  7.8 2.137 7.92 2.151 ;
     RECT  10.5 2.137 10.62 2.151 ;
     RECT  13.2 2.137 13.32 2.151 ;
     RECT  15.9 2.137 16.02 2.151 ;
     RECT  18.6 2.137 18.72 2.151 ;
     RECT  21.3 2.137 21.42 2.151 ;
     RECT  24 2.137 24.12 2.151 ;
     RECT  18.6 2.151 18.912 2.197 ;
     RECT  7.8 2.151 8.112 2.245 ;
     RECT  10.5 2.151 10.812 2.245 ;
     RECT  15.9 2.151 16.212 2.341 ;
     RECT  5.1 2.151 5.412 2.821 ;
     RECT  13.2 2.151 13.512 2.821 ;
     RECT  10.128 2.245 10.812 2.915 ;
     RECT  2.4 2.151 2.712 3.013 ;
     RECT  10.5 2.915 10.812 3.013 ;
     RECT  13.2 2.821 13.608 3.827 ;
     RECT  4.512 2.821 5.412 3.925 ;
     RECT  21.3 2.151 21.612 3.925 ;
     RECT  15.9 2.341 16.536 3.973 ;
     RECT  7.8 2.245 8.712 4.069 ;
     RECT  24 2.151 24.312 4.165 ;
     RECT  13.2 3.827 13.512 4.213 ;
     RECT  18.6 2.197 19.656 4.261 ;
     RECT  7.8 4.069 8.952 4.453 ;
     RECT  4.512 3.925 6.168 4.499 ;
     RECT  14.88 3.589 14.904 4.595 ;
     RECT  21.3 3.925 22.248 4.741 ;
     RECT  21.168 4.741 22.248 4.885 ;
     RECT  21.168 4.885 22.776 4.931 ;
     RECT  10.5 3.013 11.688 4.981 ;
     RECT  4.512 4.499 5.412 5.171 ;
     RECT  7.392 4.453 8.952 5.171 ;
     RECT  24 4.165 24.408 5.171 ;
     RECT  18.144 4.261 19.656 5.219 ;
     RECT  10.32 4.981 11.688 5.557 ;
     RECT  10.272 5.557 11.688 5.605 ;
     RECT  22.752 4.931 22.776 6.035 ;
     RECT  7.392 5.171 8.112 6.851 ;
     RECT  13.104 4.213 13.512 6.853 ;
     RECT  14.592 5.077 14.616 6.853 ;
     RECT  2.4 3.013 3.48 6.899 ;
     RECT  21.168 4.931 21.612 6.899 ;
     RECT  10.272 5.605 11.976 7.235 ;
     RECT  7.8 6.851 8.112 7.333 ;
     RECT  4.56 5.171 5.412 7.379 ;
     RECT  4.656 7.379 5.412 7.475 ;
     RECT  0.144 7.477 0.168 7.667 ;
     RECT  4.992 7.475 5.412 7.909 ;
     RECT  10.272 7.235 11.688 7.955 ;
     RECT  13.104 6.853 14.616 8.003 ;
     RECT  4.992 7.909 5.736 8.291 ;
     RECT  24 5.171 24.312 9.061 ;
     RECT  10.32 7.955 11.688 9.253 ;
     RECT  13.104 8.003 13.608 9.253 ;
     RECT  10.272 9.253 11.688 9.635 ;
     RECT  5.1 8.291 5.736 9.637 ;
     RECT  21.3 6.899 21.612 9.637 ;
     RECT  13.104 9.253 13.656 9.779 ;
     RECT  15.9 3.973 16.824 10.307 ;
     RECT  10.32 9.635 11.688 10.453 ;
     RECT  10.32 10.453 11.976 10.499 ;
     RECT  2.4 6.899 3.432 10.595 ;
     RECT  13.2 9.779 13.656 10.837 ;
     RECT  5.1 9.637 6.264 10.883 ;
     RECT  20.544 9.637 21.612 10.883 ;
     RECT  13.104 10.837 13.656 11.027 ;
     RECT  15.9 10.307 16.212 11.125 ;
     RECT  5.1 10.883 5.688 11.221 ;
     RECT  18.144 5.219 19.56 11.221 ;
     RECT  7.8 7.333 9.048 11.269 ;
     RECT  24 9.061 24.408 11.269 ;
     RECT  21.3 10.883 21.612 11.365 ;
     RECT  17.184 11.221 19.56 11.459 ;
     RECT  18.384 11.459 19.56 11.461 ;
     RECT  6.672 11.365 6.696 11.701 ;
     RECT  7.68 11.269 9.048 11.701 ;
     RECT  6.672 11.701 9.096 11.843 ;
     RECT  2.4 10.595 2.712 11.941 ;
     RECT  10.32 10.499 10.812 11.941 ;
     RECT  13.2 11.027 13.656 11.941 ;
     RECT  21.3 11.365 22.296 11.987 ;
     RECT  4.56 11.221 5.688 12.035 ;
     RECT  10.272 11.941 10.812 12.181 ;
     RECT  21.3 11.987 21.612 12.517 ;
     RECT  2.4 11.941 2.904 12.563 ;
     RECT  11.952 10.499 11.976 12.563 ;
     RECT  23.568 11.269 24.408 12.563 ;
     RECT  10.224 12.181 10.812 12.755 ;
     RECT  5.1 12.035 5.688 12.853 ;
     RECT  6.672 11.843 8.52 12.853 ;
     RECT  13.2 11.941 14.472 12.901 ;
     RECT  15.552 11.125 16.212 12.901 ;
     RECT  5.1 12.853 8.52 12.947 ;
     RECT  10.272 12.755 10.812 12.949 ;
     RECT  6.864 12.947 8.52 13.043 ;
     RECT  13.2 12.901 16.212 13.283 ;
     RECT  21.12 12.517 21.612 13.571 ;
     RECT  15.9 13.283 16.212 13.669 ;
     RECT  17.184 11.459 17.208 13.669 ;
     RECT  7.44 13.043 8.52 13.715 ;
     RECT  10.272 12.949 11.784 13.715 ;
     RECT  18.384 11.461 19.992 13.715 ;
     RECT  23.568 12.563 24.312 13.715 ;
     RECT  13.2 13.283 14.616 14.099 ;
     RECT  15.9 13.669 17.208 14.197 ;
     RECT  21.3 13.571 21.612 14.197 ;
     RECT  5.1 12.947 5.736 14.291 ;
     RECT  18.48 13.715 19.992 14.341 ;
     RECT  15.9 14.197 17.256 14.387 ;
     RECT  2.4 12.563 2.712 14.389 ;
     RECT  7.68 13.715 8.52 14.723 ;
     RECT  10.5 13.715 11.784 14.773 ;
     RECT  13.2 14.099 14.472 14.773 ;
     RECT  18.48 14.341 20.136 14.867 ;
     RECT  18.48 14.867 19.896 15.061 ;
     RECT  17.232 14.387 17.256 15.443 ;
     RECT  21.3 14.197 22.2 15.443 ;
     RECT  5.1 14.291 5.688 15.829 ;
     RECT  24 13.715 24.312 15.829 ;
     RECT  21.3 15.443 21.816 16.403 ;
     RECT  10.5 14.773 14.472 16.499 ;
     RECT  13.2 16.499 14.472 16.643 ;
     RECT  13.2 16.643 14.232 16.787 ;
     RECT  21.3 16.403 21.72 16.885 ;
     RECT  7.8 14.723 8.52 16.981 ;
     RECT  15.9 14.387 16.212 17.029 ;
     RECT  7.8 16.981 9.096 17.123 ;
     RECT  18.336 15.061 19.896 17.411 ;
     RECT  24 15.829 24.552 17.699 ;
     RECT  21.168 16.885 21.72 18.227 ;
     RECT  18.336 17.411 19.224 18.565 ;
     RECT  15.9 17.029 16.584 18.659 ;
     RECT  5.1 15.829 6.12 18.661 ;
     RECT  7.8 17.123 8.52 18.757 ;
     RECT  10.5 16.499 11.4 18.757 ;
     RECT  24 17.699 24.312 18.757 ;
     RECT  21.3 18.227 21.72 18.803 ;
     RECT  5.1 18.661 6.168 18.995 ;
     RECT  7.536 18.757 8.52 18.995 ;
     RECT  18.336 18.565 19.992 19.091 ;
     RECT  15.9 18.659 16.212 19.237 ;
     RECT  19.968 19.091 19.992 19.427 ;
     RECT  5.1 18.995 5.688 19.571 ;
     RECT  18.336 19.091 18.912 19.571 ;
     RECT  10.5 18.757 12.024 20.003 ;
     RECT  5.1 19.571 5.592 20.051 ;
     RECT  10.5 20.003 11.4 20.051 ;
     RECT  15.792 19.237 16.212 20.051 ;
     RECT  10.5 20.051 10.92 20.339 ;
     RECT  21.3 18.803 21.612 20.341 ;
     RECT  23.184 18.757 24.312 20.341 ;
     RECT  7.8 18.995 8.52 20.389 ;
     RECT  7.8 20.389 9.144 20.675 ;
     RECT  20.208 19.909 20.232 21.107 ;
     RECT  7.8 20.675 8.52 21.155 ;
     RECT  21.3 20.341 24.312 21.155 ;
     RECT  7.8 21.155 8.112 21.157 ;
     RECT  21.3 21.155 22.536 21.203 ;
     RECT  18.384 19.571 18.912 21.731 ;
     RECT  1.968 14.389 2.712 22.021 ;
     RECT  15.9 20.051 16.212 22.165 ;
     RECT  10.5 20.339 10.812 22.213 ;
     RECT  24 21.155 24.312 22.213 ;
     RECT  18.6 21.731 18.912 22.405 ;
     RECT  7.68 21.157 8.112 22.451 ;
     RECT  23.328 22.213 24.312 22.883 ;
     RECT  10.5 22.213 11.4 23.171 ;
     RECT  15.9 22.165 17.064 23.315 ;
     RECT  1.968 22.021 3.432 23.411 ;
     RECT  18.6 22.405 19.032 23.411 ;
     RECT  5.1 20.051 5.412 23.769 ;
     RECT  7.8 22.451 8.112 23.769 ;
     RECT  10.5 23.171 10.812 23.769 ;
     RECT  13.2 16.787 13.512 23.769 ;
     RECT  15.9 23.315 16.212 23.769 ;
     RECT  18.6 23.411 18.912 23.769 ;
     RECT  21.3 21.203 21.612 23.769 ;
     RECT  24 22.883 24.312 23.769 ;
     RECT  5.1 23.769 5.22 23.783 ;
     RECT  7.8 23.769 7.92 23.783 ;
     RECT  10.5 23.769 10.62 23.783 ;
     RECT  13.2 23.769 13.32 23.783 ;
     RECT  15.9 23.769 16.02 23.783 ;
     RECT  18.6 23.769 18.72 23.783 ;
     RECT  21.3 23.769 21.42 23.783 ;
     RECT  24 23.769 24.12 23.783 ;
     RECT  1.968 23.411 2.808 23.891 ;
     RECT  1.968 23.891 2.664 23.893 ;
     RECT  1.776 23.893 2.664 25.093 ;
     RECT  1.776 25.093 2.76 25.717 ;
     RECT  1.776 25.717 2.856 25.811 ;
     RECT  1.872 25.811 2.856 25.872 ;
  END
END qfd_landh0d8n_32_EW_28x26
END LIBRARY
